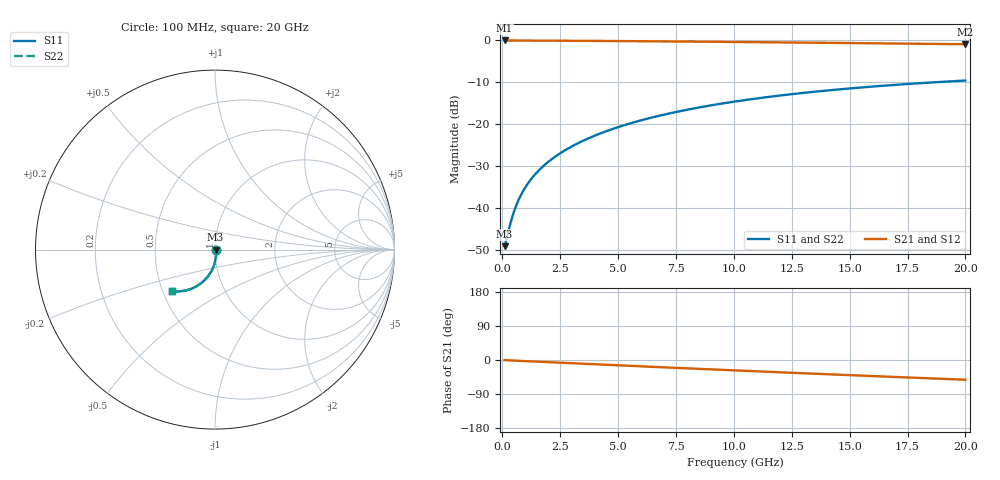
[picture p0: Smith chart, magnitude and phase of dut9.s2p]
! Touchstone file exported from HFSS 2026.1.0
!  File:  C:/ffzhzh/LocalFiles/Ansys_Project_Files/temp_test_TMRDL_9_1782906963_13352.aedt
!  Generated:  07:57:49 PM Jul  1, 2026
!  Design:  TMRDL
!  Project:  temp_test_TMRDL_9_1782906963_13352
! Variables:
!  h_bsmrdl = 2um
!  h_ox = 20um
!  h_rdl = 5um
!  h_sub = 80um
!  h_tmrdl = 4.57um
!  h_tsv = 80um
!  h_via = 3um
!  l_bsmrdl = 300um
!  l_sub = 1256.18um
!  l_tmrdl = 856.18um
!  m_sub = 200um
!  pitch = 23.03um
!  r_tsv = 6um
!  s_tmrdl = 10um
!  w_bsmrdl = 18um
!  w_sub = 500um
!  w_tmrdl = 21.47um
!  x_tsv_center1 = 866.915um
!  x_tsv_center2 = 1184.915um
!  x_tsv_center3 = 2062.565um
!  x_tsv_center4 = 2380.565um
!  x_tsv_center5 = 3258.215um
!  x_tsv_center6 = 3576.215um
# GHz S MA R 50.000000
! Terminal data exported
! Port[1] = TM_RDL1_1_T1
! Port[2] = TM_RDL1_1_T2
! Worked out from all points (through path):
!   200 points, 100 MHz to 20 GHz, reference 50 ohm
!   highest |S21| = -0.03 dB at 100 MHz (marker M1); lowest = -0.9 dB at 20 GHz (marker M2)
!   group delay of S21, straight-line fit = 7.21 ps
!   lowest |S11| = -49.0 dB at 100 MHz (marker M3), VSWR 1.01, Z = 50.3 - j0.076 ohm
!   |S11| at or under -10 dB: start of sweep to 18.63 GHz
!   |S22| runs from -49.0 to -9.6 dB; largest |S21 - S12| = 2.9e-14
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0.1  0.003544 -12.3  0.9965 -0.3  0.9965 -0.3  0.003544 -12.3
! Gamma 0 0 0 0
! Port Impedance 50 0 50 0
0.4  0.007391 -43.5  0.9945 -1.3  0.9945 -1.3  0.007391 -43.5
0.5  0.009056 -50.3  0.994 -1.5  0.994 -1.5  0.009056 -50.3
0.6  0.01078 -55.6  0.9936 -1.8  0.9936 -1.8  0.01078 -55.7
0.7  0.01253 -59.9  0.9933 -2.1  0.9933 -2.1  0.01253 -59.9
0.9  0.01609 -66.3  0.9928 -2.7  0.9928 -2.7  0.01609 -66.3
1.2  0.02148 -72.6  0.9921 -3.5  0.9921 -3.5  0.02148 -72.6
1.4  0.02509 -75.5  0.9917 -4.1  0.9917 -4.1  0.02509 -75.5
1.7  0.03054 -78.8  0.9911 -4.9  0.9911 -4.9  0.03054 -78.8
2.2  0.03971 -82.7  0.9899 -6.3  0.9899 -6.3  0.03971 -82.7
2.8  0.05083 -86.1  0.9882 -8.0  0.9882 -8.0  0.05083 -86.1
3.5  0.06398 -89.2  0.986 -9.9  0.986 -9.9  0.06398 -89.2
4.2  0.07727 -91.8  0.9834 -11.9  0.9834 -11.9  0.07727 -91.8
5  0.09257 -94.6  0.9803 -14.1  0.9803 -14.1  0.09256 -94.6
5.9  0.1098 -97.5  0.9765 -16.5  0.9765 -16.5  0.1098 -97.5
6.8  0.127 -100.3  0.9725 -18.9  0.9725 -18.9  0.127 -100.4
8.3  0.1551 -104.9  0.9654 -22.9  0.9654 -22.9  0.1551 -104.9
10.1  0.1877 -110.1  0.9562 -27.6  0.9562 -27.6  0.1877 -110.1
11.7  0.2153 -114.6  0.9475 -31.7  0.9475 -31.7  0.2153 -114.6
13.4  0.243 -119.2  0.9378 -36.0  0.9378 -36.0  0.243 -119.2
16.7  0.2914 -127.7  0.9181 -44.2  0.9181 -44.2  0.2914 -127.7
20  0.3323 -135.8  0.8982 -52.0  0.8982 -52.0  0.3323 -135.8
